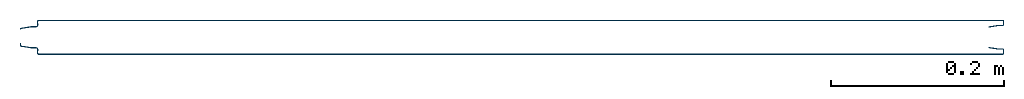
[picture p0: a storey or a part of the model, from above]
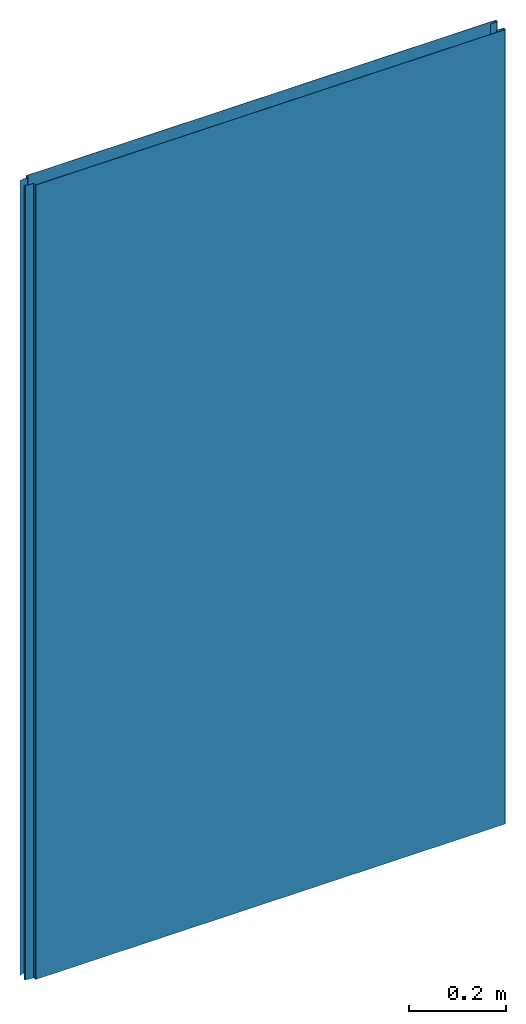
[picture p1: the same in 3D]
Properties of the parts of a building model (IFC2X3)

# File
Description: ViewDefinition [CoordinationView_V2.0]
File name: 0001
Time: 2026-05-13T12:59:57
Written by: The EXPRESS Data Manager Version 5.02.0100.07 : 28 Aug 2013
Made in: 21.1.1.109 - Exporter 21.1.1.109 - IU alternativa 21.1.1.109
Comment: STEP Physical File produced by: The EXPRESS Data Manager Version 5.02.0100.07 : 28 Aug 2013 * Module: EDMstepFileFactory/EDMstandAlone * Creation date: Wed May 13 12:59:57 2026 * Host: PT56 * Database: C:\Users\malonso\AppData\Local\Temp\c087ce03-56e2-4a18-ba95-85b50aca9593\66f6feb6-fbee-48a6-80e8-a13a12488367\ifc * Database version: 5507 * Database creation date: Wed May 13 12:59:56 2026 * Schema: IFC2X3 * Model: DataRepository.ifc * Model creation date: Wed May 13 12:59:56 2026 * Header model: DataRepository.ifc_HeaderModel * Header model creation date: Wed May 13 12:59:56 2026 * EDMuser: sdai-user * EDMgroup: sdai-group * License ID and type: 5605 : Permanent license. Expiry date: * EDMstepFileFactory options: 020000

# IfcProject, 0001
LongName: Nombre de proyecto; Phase: Estado de proyecto

# IfcSite, Default
RefLatitude: 40, 25, 13, 9643; RefLongitude: -3, -42, -20, -772056; RefElevation: 0 m
Otros - Categoría: Información de proyecto; Dirección de proyecto: Introduzca dirección aquí; Estado de proyecto: Estado de proyecto; Fecha de emisión de proyecto: Fecha de emisión; Nombre de cliente: Propietario; Nombre de proyecto: Nombre de proyecto; Número de proyecto: 0001

# IfcBuilding
Otros - Categoría: Información de proyecto; Dirección de proyecto: Introduzca dirección aquí; Estado de proyecto: Estado de proyecto; Fecha de emisión de proyecto: Fecha de emisión; Nombre de cliente: Propietario; Nombre de proyecto: Nombre de proyecto; Número de proyecto: 0001

# IfcBuildingStorey: Nivel:Nivel 1, Nivel 1
LongName: Nivel 1; Elevation: 0 m
Restricciones(Type) - Base de elevación: Punto base del proyecto
Otros(Type) - Categoría: Niveles; Nombre de familia: Nivel
Cotas - Altura de cálculo: 0 m
Datos de identidad - Estructura: no; Nombre: Nivel 1; Planta de edificio: yes
Otros - Categoría: Niveles; Familia: Nivel: Nivel 1; Familia y tipo: Nivel: Nivel 1; ID de tipo: Nivel: Nivel 1; Tipo: Nivel: Nivel 1
Restricciones - Alzado: 0 m
Datos de identidad(Type) - Nombre de tipo: Nivel 1
Gráficos(Type) - Color: 0; Grosor de línea: 1; Patrón de línea: Trazo punto; Símbolo: Extremo de nivel: Extremo de nivel; Símbolo en extremo 1 por defecto: no; Símbolo en extremo 2 por defecto: yes

# IfcWallStandardCase: Panel_HI_QuadCore 2.0 F40_liso-liso:HI-Quadcore 2.0 F40 liso-liso, Panel_HI_QuadCore 2.0 F40_liso-liso:HI-Quadcore 2.0 F40 liso-liso:169723
In: Nivel 1
Type - Material: QuadCore 2.0, Acero estructural S220GD
Type - Análisis energético - Clasificación reacción ante el fuego: Euroclase B,s1,d0; Conductividad térmica declarada: 0.019; Permeabilidad al agua: CLASE A (1,800Pa). Acorde a la norma UNE-EN 12865:2002. Valores válidos para espesores igual o superior a 80mm.; Permeabilidad al aire: 0,00m3/h· m2 a 50Pa. Acorde a norma UNE-EN 12114:2000. Valores válidos para espesores igual o superior a 80mm.; Resistencia térmica: 2.22; Transmitancia térmica: 0.46
Type - Construcción - Espesor limite: 0.04 m
Type - Cotas - Ancho Útil: 1.12 m; Espesor: 0.04 m
Type - Datos - Aplicación: Paredes, Techos y particiones; Certificados: Marcado CE, FM Approval; Espesor de la chapa disponibles (mm): Exterior [0.5, 0.6, 0.7], Interior [0.5, 0.6, 0.7]; Información técnica: https://www.huurreiberica.com/producto/hi-quadcore-2-0-f40/; Recubrimientos: Consultar ficha tecnica
Type - Datos de identidad - Fabricante: Huurre Iberica; Garantia: Hasta 25 años prestaciones funcionales, hasta 35 años para sus recubrimientos; Modelo: HI-Quadcore 2.0 F40; Nombre de tipo: HI-Quadcore 2.0 F40 liso-liso; Normas de referencia: UNE-EN 14509:2014 para paneles, UNE EN 10327:2007 para recubrimiento galvanizado, UNE EN 10169:2011 para recubrimientos orgánicos; Número OmniClass: 23.25.30.24.21; Referencia de producto: HI-QuadCore 2.0 F 40; Título OmniClass: Metal Framed Structural Walls; URL: www.huurreiberica.com
Type - Materiales y acabados - Material cara exterior e interior: Acero estructural S220GD; Material núcleo aislante: QuadCore 2.0; Perfilado cara exterior: Liso; Perfilado cara interior: Liso; Peso (kg): 9.85; Tipo de junta: DJ
Type - Otros - Categoría: Modelos genéricos; Nombre de familia: Panel_HI_QuadCore 2.0 F40_liso-liso
Type - Restricciones - Elevación por defecto: 0 m
Material: Acero estructural S220GD, QuadCore 2.0
Construcción - Altura paneles: 2 m; Altura paneles limte: 2 m
Cotas - Área: 7.10378 m2; Volumen: 0.0895272 m3
Datos - Longitud de fabricación Especial (m): 13,5 a 18 m (transporte especial); Longitud de fabricación Estándar (m): 2,0 a 13,5 m
Otros - Familia: Panel_HI_QuadCore 2.0 F40_liso-liso: HI-Quadcore 2.0 F40 liso-liso; Familia y tipo: Panel_HI_QuadCore 2.0 F40_liso-liso: HI-Quadcore 2.0 F40 liso-liso; ID de tipo: Panel_HI_QuadCore 2.0 F40_liso-liso: HI-Quadcore 2.0 F40 liso-liso; Tipo: Panel_HI_QuadCore 2.0 F40_liso-liso: HI-Quadcore 2.0 F40 liso-liso
Proceso por fases - Fase de creación: Nueva construcción
Restricciones - Anfitrión: Nivel : Nivel 1; Desfase desde el anfitrión: 0 m; Elevación desde el nivel: 0 m; Nivel: Nivel: Nivel 1; Se mueve con elementos cercanos: no
